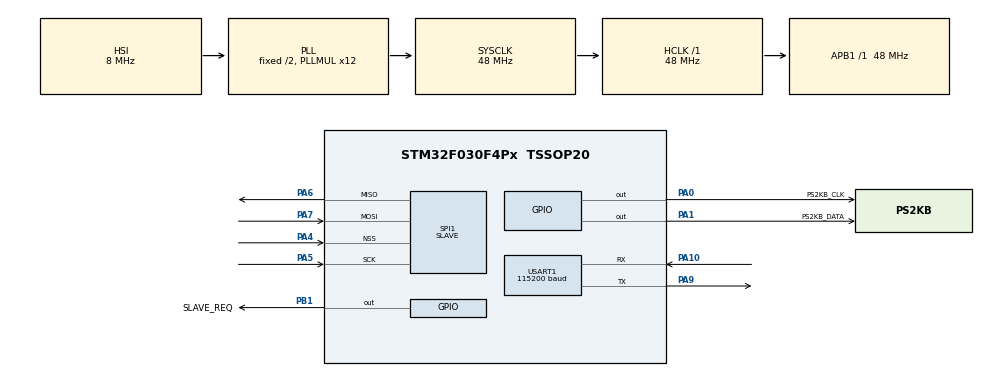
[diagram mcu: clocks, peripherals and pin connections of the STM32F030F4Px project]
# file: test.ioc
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Mcu.Family=STM32F0
Mcu.Name=STM32F030F4Px
Mcu.Package=TSSOP20
NVIC.SPI1_IRQn=true\:0\:0\:false\:false\:true\:true
NVIC.TIM14_IRQn=true\:1\:0\:true\:false\:true\:true
PA0.GPIO_Label=PS2KB_CLK
PA0.GPIO_ModeDefaultOutputPP=GPIO_MODE_OUTPUT_OD
PA0.PinState=GPIO_PIN_SET
PA0.Signal=GPIO_Output
PA1.GPIO_Label=PS2KB_DATA
PA1.GPIO_ModeDefaultOutputPP=GPIO_MODE_OUTPUT_OD
PA1.PinState=GPIO_PIN_SET
PA1.Signal=GPIO_Output
PA10.Mode=Asynchronous
PA10.Signal=USART1_RX
PA13.Mode=Serial_Wire
PA13.Signal=SYS_SWDIO
PA14.Mode=Serial_Wire
PA14.Signal=SYS_SWCLK
PA4.Mode=NSS_Signal_Hard_Input
PA4.Signal=SPI1_NSS
PA5.Mode=Full_Duplex_Slave
PA5.Signal=SPI1_SCK
PA6.Mode=Full_Duplex_Slave
PA6.Signal=SPI1_MISO
PA7.Mode=Full_Duplex_Slave
PA7.Signal=SPI1_MOSI
PA9.Mode=Asynchronous
PA9.Signal=USART1_TX
PB1.GPIO_Label=SLAVE_REQ
PB1.Signal=GPIO_Output
ProjectManager.HeapSize=0x200
ProjectManager.StackSize=0x400
ProjectManager.TargetToolchain=MDK-ARM V5
RCC.AHBFreq_Value=48000000
RCC.APB1Freq_Value=48000000
RCC.APB1TimFreq_Value=48000000
RCC.HCLKFreq_Value=48000000
RCC.PLLMUL=RCC_PLL_MUL12
RCC.SYSCLKFreq_VALUE=48000000
RCC.SYSCLKSource=RCC_SYSCLKSOURCE_PLLCLK
SPI1.DataSize=SPI_DATASIZE_8BIT
SPI1.Direction=SPI_DIRECTION_2LINES
SPI1.Mode=SPI_MODE_SLAVE
SPI1.VirtualNSS=VM_NSSHARD
SPI1.VirtualType=VM_SLAVE
TIM14.Period=65535
TIM14.Prescaler=47
USART1.BaudRate=115200
USART1.VirtualMode-Asynchronous=VM_ASYNC
VP_TIM14_VS_ClockSourceINT.Mode=Enable_Timer
board=test

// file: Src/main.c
/**
  ******************************************************************************
  * @file           : main.c
  * @brief          : Main program body
  ******************************************************************************
  ** This notice applies to any and all portions of this file
  * that are not between comment pairs USER CODE BEGIN and
  * USER CODE END. Other portions of this file, whether
  * inserted by the user or by software development tools
  * are owned by their respective copyright owners.
  *
  * COPYRIGHT(c) 2021 STMicroelectronics
  *
  * Redistribution and use in source and binary forms, with or without modification,
  * are permitted provided that the following conditions are met:
  *   1. Redistributions of source code must retain the above copyright notice,
  *      this list of conditions and the following disclaimer.
  *   2. Redistributions in binary form must reproduce the above copyright notice,
  *      this list of conditions and the following disclaimer in the documentation
  *      and/or other materials provided with the distribution.
  *   3. Neither the name of STMicroelectronics nor the names of its contributors
  *      may be used to endorse or promote products derived from this software
  *      without specific prior written permission.
  *
  * THIS SOFTWARE IS PROVIDED BY THE COPYRIGHT HOLDERS AND CONTRIBUTORS "AS IS"
  * AND ANY EXPRESS OR IMPLIED WARRANTIES, INCLUDING, BUT NOT LIMITED TO, THE
  * IMPLIED WARRANTIES OF MERCHANTABILITY AND FITNESS FOR A PARTICULAR PURPOSE ARE
  * DISCLAIMED. IN NO EVENT SHALL THE COPYRIGHT HOLDER OR CONTRIBUTORS BE LIABLE
  * FOR ANY DIRECT, INDIRECT, INCIDENTAL, SPECIAL, EXEMPLARY, OR CONSEQUENTIAL
  * DAMAGES (INCLUDING, BUT NOT LIMITED TO, PROCUREMENT OF SUBSTITUTE GOODS OR
  * SERVICES; LOSS OF USE, DATA, OR PROFITS; OR BUSINESS INTERRUPTION) HOWEVER
  * CAUSED AND ON ANY THEORY OF LIABILITY, WHETHER IN CONTRACT, STRICT LIABILITY,
  * OR TORT (INCLUDING NEGLIGENCE OR OTHERWISE) ARISING IN ANY WAY OUT OF THE USE
  * OF THIS SOFTWARE, EVEN IF ADVISED OF THE POSSIBILITY OF SUCH DAMAGE.
  *
  ******************************************************************************
  */
#include "main.h"
#include "stm32f0xx_hal.h"

/* USER CODE BEGIN Includes */
#include "shared.h"
#include "helpers.h"
#include "delay_us.h"
#include "ps2kb.h"
#include <string.h>
/* USER CODE END Includes */

SPI_HandleTypeDef hspi1;

TIM_HandleTypeDef htim14;

UART_HandleTypeDef huart1;

/* USER CODE BEGIN PV */
/* Private variables ---------------------------------------------------------*/
uint8_t spi_transmit_buf[SPI_BUF_SIZE];

uint8_t spi_out_of_sync;
uint8_t backup_spi1_recv_buf[SPI_BUF_SIZE];

/* USER CODE END PV */

void SystemClock_Config(void);
static void MX_GPIO_Init(void);
static void MX_USART1_UART_Init(void);
static void MX_TIM14_Init(void);
static void MX_SPI1_Init(void);

/* USER CODE BEGIN PFP */
/* Private function prototypes -----------------------------------------------*/

/* USER CODE END PFP */

/* USER CODE BEGIN 0 */
int fputc(int ch, FILE *f)
{
    HAL_UART_Transmit(&huart1, (unsigned char *)&ch, 1, 100);
    return ch;
}

void HAL_SPI_TxRxCpltCallback(SPI_HandleTypeDef *hspi)
{
  HAL_GPIO_WritePin(DEBUG_GPIO_Port, DEBUG_Pin, GPIO_PIN_SET);
  memcpy(backup_spi1_recv_buf, spi_recv_buf, SPI_BUF_SIZE);
  HAL_SPI_TransmitReceive_IT(&hspi1, spi_transmit_buf, spi_recv_buf, SPI_BUF_SIZE);

  // if(backup_spi1_recv_buf[SPI_BUF_INDEX_MAGIC] != SPI_MOSI_MAGIC)
  // {
  //   printf("WRONG\n");
  //   spi_out_of_sync = 1;
  //   return;
  // }

  if(backup_spi1_recv_buf[SPI_BUF_INDEX_MSG_TYPE] == SPI_MOSI_MSG_KB_EVENT)
    ps2kb_buf_add(&my_ps2kb_buf, backup_spi1_recv_buf[6], backup_spi1_recv_buf[8]);

  if(backup_spi1_recv_buf[SPI_BUF_INDEX_MSG_TYPE] == SPI_MOSI_MSG_REQ_ACK)
    HAL_GPIO_WritePin(SLAVE_REQ_GPIO_Port, SLAVE_REQ_Pin, GPIO_PIN_RESET);
  HAL_GPIO_WritePin(DEBUG_GPIO_Port, DEBUG_Pin, GPIO_PIN_RESET);
}

/* USER CODE END 0 */

int main(void)
{

  /* MCU Configuration----------------------------------------------------------*/

  /* Reset of all peripherals, Initializes the Flash interface and the Systick. */
  HAL_Init();

  /* Configure the system clock */
  SystemClock_Config();

  /* Initialize all configured peripherals */
  MX_GPIO_Init();
  MX_USART1_UART_Init();
  MX_TIM14_Init();
  MX_SPI1_Init();

  /* Infinite loop */
  /* USER CODE BEGIN WHILE */
  delay_us_init(&htim14);
  ps2kb_init(PS2KB_CLK_GPIO_Port, PS2KB_CLK_Pin, PS2KB_DATA_GPIO_Port, PS2KB_DATA_Pin);
  uint8_t ps2kb_host_cmd, ps2kb_leds;
  ps2kb_buf_init(&my_ps2kb_buf, 16);
  memset(spi_transmit_buf, 0, SPI_BUF_SIZE);
  HAL_SPI_TransmitReceive_IT(&hspi1, spi_transmit_buf, spi_recv_buf, SPI_BUF_SIZE);
  printf("hello world\n");

  while (1)
  {

  /* USER CODE END WHILE */

  /* USER CODE BEGIN 3 */

    // if(spi_out_of_sync)
    // {
    //   HAL_SPI_Abort(&hspi1);
    //   while(HAL_GPIO_ReadPin(GPIOA, GPIO_PIN_4) == GPIO_PIN_RESET);
    //   HAL_Delay(2);
    //   HAL_SPI_TransmitReceive_IT(&hspi1, spi_transmit_buf, spi_recv_buf, SPI_BUF_SIZE);
    //   spi_out_of_sync = 0;
    // }

    // if(ps2kb_get_bus_status() == PS2_BUS_REQ_TO_SEND)
    // {
    //   ps2kb_leds = 0xff;
    //   ps2kb_read(&ps2kb_host_cmd, 10);
    //   keyboard_reply(ps2kb_host_cmd, &ps2kb_leds);
    //   if(ps2kb_leds != 0xff)
    //   {
    //     memset(spi_transmit_buf, 0, SPI_BUF_SIZE);
    //     spi_transmit_buf[SPI_BUF_INDEX_MAGIC] = SPI_MISO_MAGIC;
    //     spi_transmit_buf[SPI_BUF_INDEX_SEQNUM] = backup_spi1_recv_buf[SPI_BUF_INDEX_SEQNUM];
    //     spi_transmit_buf[SPI_BUF_INDEX_MSG_TYPE] = SPI_MISO_MSG_KB_LED_REQ;
    //     spi_transmit_buf[3] = ps2kb_leds;
    //     HAL_GPIO_WritePin(SLAVE_REQ_GPIO_Port, SLAVE_REQ_Pin, GPIO_PIN_SET);
    //   }
    // }

    // uint8_t buffered_code, buffered_value;
    // if(ps2kb_buf_get(&my_ps2kb_buf, &buffered_code, &buffered_value) == 0)
    // {
    //   // if SPI is active, wait for it to finish
    //   while(HAL_GPIO_ReadPin(GPIOA, GPIO_PIN_4) == GPIO_PIN_RESET);
    //   HAL_SPI_TransmitReceive_IT(&hspi1, spi_transmit_buf, spi_recv_buf, SPI_BUF_SIZE);
    //   ps2kb_press_key(buffered_code, buffered_value);
    //   HAL_SPI_TransmitReceive_IT(&hspi1, spi_transmit_buf, spi_recv_buf, SPI_BUF_SIZE);
    // }

  }
  /* USER CODE END 3 */

}

void SystemClock_Config(void)
{

  RCC_OscInitTypeDef RCC_OscInitStruct;
  RCC_ClkInitTypeDef RCC_ClkInitStruct;
  RCC_PeriphCLKInitTypeDef PeriphClkInit;

    /**Initializes the CPU, AHB and APB busses clocks
    */
  RCC_OscInitStruct.OscillatorType = RCC_OSCILLATORTYPE_HSI;
  RCC_OscInitStruct.HSIState = RCC_HSI_ON;
  RCC_OscInitStruct.HSICalibrationValue = 16;
  RCC_OscInitStruct.PLL.PLLState = RCC_PLL_ON;
  RCC_OscInitStruct.PLL.PLLSource = RCC_PLLSOURCE_HSI;
  RCC_OscInitStruct.PLL.PLLMUL = RCC_PLL_MUL12;
  RCC_OscInitStruct.PLL.PREDIV = RCC_PREDIV_DIV1;
  if (HAL_RCC_OscConfig(&RCC_OscInitStruct) != HAL_OK)
  {
    _Error_Handler(__FILE__, __LINE__);
  }

    /**Initializes the CPU, AHB and APB busses clocks
    */
  RCC_ClkInitStruct.ClockType = RCC_CLOCKTYPE_HCLK|RCC_CLOCKTYPE_SYSCLK
                              |RCC_CLOCKTYPE_PCLK1;
  RCC_ClkInitStruct.SYSCLKSource = RCC_SYSCLKSOURCE_PLLCLK;
  RCC_ClkInitStruct.AHBCLKDivider = RCC_SYSCLK_DIV1;
  RCC_ClkInitStruct.APB1CLKDivider = RCC_HCLK_DIV1;

  if (HAL_RCC_ClockConfig(&RCC_ClkInitStruct, FLASH_LATENCY_1) != HAL_OK)
  {
    _Error_Handler(__FILE__, __LINE__);
  }

  PeriphClkInit.PeriphClockSelection = RCC_PERIPHCLK_USART1;
  PeriphClkInit.Usart1ClockSelection = RCC_USART1CLKSOURCE_PCLK1;
  if (HAL_RCCEx_PeriphCLKConfig(&PeriphClkInit) != HAL_OK)
  {
    _Error_Handler(__FILE__, __LINE__);
  }

    /**Configure the Systick interrupt time
    */
  HAL_SYSTICK_Config(HAL_RCC_GetHCLKFreq()/1000);

    /**Configure the Systick
    */
  HAL_SYSTICK_CLKSourceConfig(SYSTICK_CLKSOURCE_HCLK);

  /* SysTick_IRQn interrupt configuration */
  HAL_NVIC_SetPriority(SysTick_IRQn, 0, 0);
}

/* SPI1 init function */
static void MX_SPI1_Init(void)
{

  /* SPI1 parameter configuration*/
  hspi1.Instance = SPI1;
  hspi1.Init.Mode = SPI_MODE_SLAVE;
  hspi1.Init.Direction = SPI_DIRECTION_2LINES;
  hspi1.Init.DataSize = SPI_DATASIZE_8BIT;
  hspi1.Init.CLKPolarity = SPI_POLARITY_LOW;
  hspi1.Init.CLKPhase = SPI_PHASE_1EDGE;
  hspi1.Init.NSS = SPI_NSS_HARD_INPUT;
  hspi1.Init.FirstBit = SPI_FIRSTBIT_MSB;
  hspi1.Init.TIMode = SPI_TIMODE_DISABLE;
  hspi1.Init.CRCCalculation = SPI_CRCCALCULATION_DISABLE;
  hspi1.Init.CRCPolynomial = 7;
  hspi1.Init.CRCLength = SPI_CRC_LENGTH_DATASIZE;
  hspi1.Init.NSSPMode = SPI_NSS_PULSE_DISABLE;
  if (HAL_SPI_Init(&hspi1) != HAL_OK)
  {
    _Error_Handler(__FILE__, __LINE__);
  }

}

/* TIM14 init function */
static void MX_TIM14_Init(void)
{

  htim14.Instance = TIM14;
  htim14.Init.Prescaler = 47;
  htim14.Init.CounterMode = TIM_COUNTERMODE_UP;
  htim14.Init.Period = 65535;
  htim14.Init.ClockDivision = TIM_CLOCKDIVISION_DIV1;
  htim14.Init.AutoReloadPreload = TIM_AUTORELOAD_PRELOAD_DISABLE;
  if (HAL_TIM_Base_Init(&htim14) != HAL_OK)
  {
    _Error_Handler(__FILE__, __LINE__);
  }

}

/* USART1 init function */
static void MX_USART1_UART_Init(void)
{

  huart1.Instance = USART1;
  huart1.Init.BaudRate = 115200;
  huart1.Init.WordLength = UART_WORDLENGTH_8B;
  huart1.Init.StopBits = UART_STOPBITS_1;
  huart1.Init.Parity = UART_PARITY_NONE;
  huart1.Init.Mode = UART_MODE_TX_RX;
  huart1.Init.HwFlowCtl = UART_HWCONTROL_NONE;
  huart1.Init.OverSampling = UART_OVERSAMPLING_16;
  huart1.Init.OneBitSampling = UART_ONE_BIT_SAMPLE_DISABLE;
  huart1.AdvancedInit.AdvFeatureInit = UART_ADVFEATURE_NO_INIT;
  if (HAL_UART_Init(&huart1) != HAL_OK)
  {
    _Error_Handler(__FILE__, __LINE__);
  }

}

/** Configure pins as
        * Analog
        * Input
        * Output
        * EVENT_OUT
        * EXTI
*/
static void MX_GPIO_Init(void)
{

  GPIO_InitTypeDef GPIO_InitStruct;

  /* GPIO Ports Clock Enable */
  __HAL_RCC_GPIOA_CLK_ENABLE();
  __HAL_RCC_GPIOB_CLK_ENABLE();

  /*Configure GPIO pin Output Level */
  HAL_GPIO_WritePin(GPIOA, PS2KB_CLK_Pin|PS2KB_DATA_Pin, GPIO_PIN_SET);

  /*Configure GPIO pin Output Level */
  HAL_GPIO_WritePin(GPIOA, ERROR_Pin|DEBUG_Pin, GPIO_PIN_RESET);

  /*Configure GPIO pin Output Level */
  HAL_GPIO_WritePin(SLAVE_REQ_GPIO_Port, SLAVE_REQ_Pin, GPIO_PIN_RESET);

  /*Configure GPIO pins : PS2KB_CLK_Pin PS2KB_DATA_Pin */
  GPIO_InitStruct.Pin = PS2KB_CLK_Pin|PS2KB_DATA_Pin;
  GPIO_InitStruct.Mode = GPIO_MODE_OUTPUT_OD;
  GPIO_InitStruct.Pull = GPIO_NOPULL;
  GPIO_InitStruct.Speed = GPIO_SPEED_FREQ_LOW;
  HAL_GPIO_Init(GPIOA, &GPIO_InitStruct);

  /*Configure GPIO pins : ERROR_Pin DEBUG_Pin */
  GPIO_InitStruct.Pin = ERROR_Pin|DEBUG_Pin;
  GPIO_InitStruct.Mode = GPIO_MODE_OUTPUT_PP;
  GPIO_InitStruct.Pull = GPIO_NOPULL;
  GPIO_InitStruct.Speed = GPIO_SPEED_FREQ_LOW;
  HAL_GPIO_Init(GPIOA, &GPIO_InitStruct);

  /*Configure GPIO pin : SLAVE_REQ_Pin */
  GPIO_InitStruct.Pin = SLAVE_REQ_Pin;
  GPIO_InitStruct.Mode = GPIO_MODE_OUTPUT_PP;
  GPIO_InitStruct.Pull = GPIO_NOPULL;
  GPIO_InitStruct.Speed = GPIO_SPEED_FREQ_LOW;
  HAL_GPIO_Init(SLAVE_REQ_GPIO_Port, &GPIO_InitStruct);

}

void _Error_Handler(char *file, int line)
{
  while(1)
  {
  }
}

/************************ (C) COPYRIGHT STMicroelectronics *****END OF FILE****/
